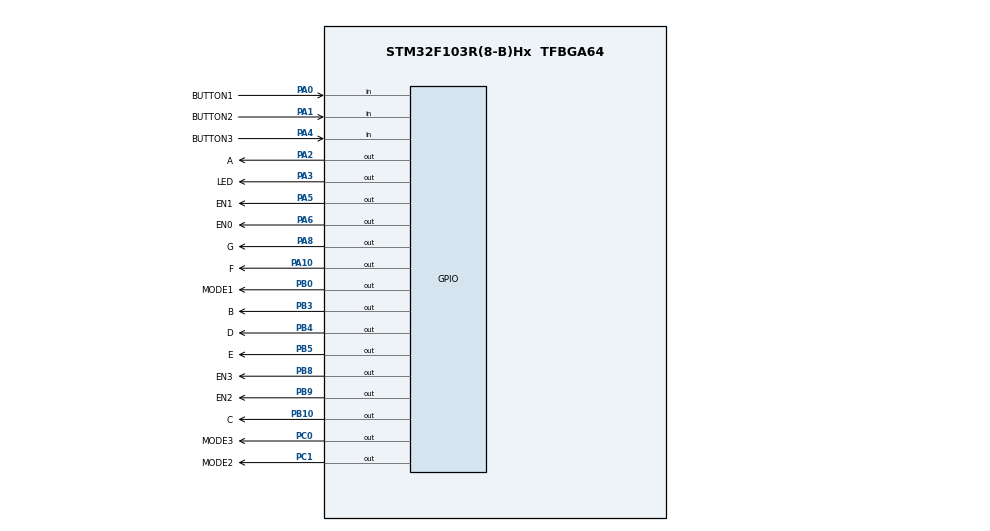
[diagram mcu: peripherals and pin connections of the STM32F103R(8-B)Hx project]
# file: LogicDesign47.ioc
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Mcu.Family=STM32F1
Mcu.Name=STM32F103R(8-B)Hx
Mcu.Package=TFBGA64
NVIC.PriorityGroup=NVIC_PRIORITYGROUP_4
NVIC.TIM2_IRQn=true\:0\:0\:false\:false\:true\:true\:true
PA0-WKUP.GPIO_Label=BUTTON1
PA0-WKUP.GPIO_PuPd=GPIO_PULLUP
PA0-WKUP.Signal=GPIO_Input
PA1.GPIO_Label=BUTTON2
PA1.GPIO_PuPd=GPIO_PULLUP
PA1.Signal=GPIO_Input
PA10.GPIO_Label=F
PA10.Signal=GPIO_Output
PA13.Mode=Serial_Wire
PA13.Signal=SYS_JTMS-SWDIO
PA14.Mode=Serial_Wire
PA14.Signal=SYS_JTCK-SWCLK
PA2.GPIO_Label=A
PA2.Signal=GPIO_Output
PA3.GPIO_Label=LED
PA3.Signal=GPIO_Output
PA4.GPIO_Label=BUTTON3
PA4.GPIO_PuPd=GPIO_PULLUP
PA4.Signal=GPIO_Input
PA5.GPIO_Label=EN1
PA5.Signal=GPIO_Output
PA6.GPIO_Label=EN0
PA6.Signal=GPIO_Output
PA8.GPIO_Label=G
PA8.Signal=GPIO_Output
PB0.GPIO_Label=MODE1
PB0.Signal=GPIO_Output
PB10.GPIO_Label=C
PB10.Signal=GPIO_Output
PB3.GPIO_Label=B
PB3.Signal=GPIO_Output
PB4.GPIO_Label=D
PB4.Signal=GPIO_Output
PB5.GPIO_Label=E
PB5.Signal=GPIO_Output
PB8.GPIO_Label=EN3
PB8.Signal=GPIO_Output
PB9.GPIO_Label=EN2
PB9.Signal=GPIO_Output
PC0.GPIO_Label=MODE3
PC0.Signal=GPIO_Output
PC1.GPIO_Label=MODE2
PC1.Signal=GPIO_Output
ProjectManager.HeapSize=0x200
ProjectManager.StackSize=0x400
ProjectManager.TargetToolchain=STM32CubeIDE
RCC.APB1Freq_Value=8000000
RCC.APB2Freq_Value=8000000
TIM2.Period=9
TIM2.Prescaler=7999
VP_TIM2_VS_ClockSourceINT.Mode=Internal
board=custom

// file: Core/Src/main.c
/* USER CODE BEGIN Header */
/**
  ******************************************************************************
  * @file           : main.c
  * @brief          : Main program body
  ******************************************************************************
  * @attention
  *
  * <h2><center>&copy; Copyright (c) 2023 STMicroelectronics.
  * All rights reserved.</center></h2>
  *
  * This software component is licensed by ST under BSD 3-Clause license,
  * the "License"; You may not use this file except in compliance with the
  * License. You may obtain a copy of the License at:
  *                        opensource.org/licenses/BSD-3-Clause
  *
  ******************************************************************************
  */
/* USER CODE END Header */
#include <driver.h>
#include "main.h"

/* USER CODE BEGIN Includes */
#include "software_timer.h"
#include "control_led_matrix.h"
#include "button.h"
/* USER CODE END Includes */

TIM_HandleTypeDef htim2;

void SystemClock_Config(void);
static void MX_GPIO_Init(void);
static void MX_TIM2_Init(void);

int main(void)
{

  /* MCU Configuration--------------------------------------------------------*/

  /* Reset of all peripherals, Initializes the Flash interface and the Systick. */
  HAL_Init();

  /* Configure the system clock */
  SystemClock_Config();

  /* Initialize all configured peripherals */
  MX_GPIO_Init();
  MX_TIM2_Init();
  /* USER CODE BEGIN 2 */
  HAL_TIM_Base_Start_IT (& htim2 );
  /* USER CODE END 2 */

  /* Infinite loop */
  /* USER CODE BEGIN WHILE */
  while (1)
  {
	 controlLedMatrix();
    /* USER CODE END WHILE */

  }
}

void SystemClock_Config(void)
{
  RCC_OscInitTypeDef RCC_OscInitStruct = {0};
  RCC_ClkInitTypeDef RCC_ClkInitStruct = {0};

  /** Initializes the RCC Oscillators according to the specified parameters
  * in the RCC_OscInitTypeDef structure.
  */
  RCC_OscInitStruct.OscillatorType = RCC_OSCILLATORTYPE_HSI;
  RCC_OscInitStruct.HSIState = RCC_HSI_ON;
  RCC_OscInitStruct.HSICalibrationValue = RCC_HSICALIBRATION_DEFAULT;
  RCC_OscInitStruct.PLL.PLLState = RCC_PLL_NONE;
  if (HAL_RCC_OscConfig(&RCC_OscInitStruct) != HAL_OK)
  {
    Error_Handler();
  }
  /** Initializes the CPU, AHB and APB buses clocks
  */
  RCC_ClkInitStruct.ClockType = RCC_CLOCKTYPE_HCLK|RCC_CLOCKTYPE_SYSCLK
                              |RCC_CLOCKTYPE_PCLK1|RCC_CLOCKTYPE_PCLK2;
  RCC_ClkInitStruct.SYSCLKSource = RCC_SYSCLKSOURCE_HSI;
  RCC_ClkInitStruct.AHBCLKDivider = RCC_SYSCLK_DIV1;
  RCC_ClkInitStruct.APB1CLKDivider = RCC_HCLK_DIV1;
  RCC_ClkInitStruct.APB2CLKDivider = RCC_HCLK_DIV1;

  if (HAL_RCC_ClockConfig(&RCC_ClkInitStruct, FLASH_LATENCY_0) != HAL_OK)
  {
    Error_Handler();
  }
}

static void MX_TIM2_Init(void)
{

  TIM_ClockConfigTypeDef sClockSourceConfig = {0};
  TIM_MasterConfigTypeDef sMasterConfig = {0};

  htim2.Instance = TIM2;
  htim2.Init.Prescaler = 799;
  htim2.Init.CounterMode = TIM_COUNTERMODE_UP;
  htim2.Init.Period = 9;
  htim2.Init.ClockDivision = TIM_CLOCKDIVISION_DIV1;
  htim2.Init.AutoReloadPreload = TIM_AUTORELOAD_PRELOAD_DISABLE;
  if (HAL_TIM_Base_Init(&htim2) != HAL_OK)
  {
    Error_Handler();
  }
  sClockSourceConfig.ClockSource = TIM_CLOCKSOURCE_INTERNAL;
  if (HAL_TIM_ConfigClockSource(&htim2, &sClockSourceConfig) != HAL_OK)
  {
    Error_Handler();
  }
  sMasterConfig.MasterOutputTrigger = TIM_TRGO_RESET;
  sMasterConfig.MasterSlaveMode = TIM_MASTERSLAVEMODE_DISABLE;
  if (HAL_TIMEx_MasterConfigSynchronization(&htim2, &sMasterConfig) != HAL_OK)
  {
    Error_Handler();
  }

}

static void MX_GPIO_Init(void)
{
  GPIO_InitTypeDef GPIO_InitStruct = {0};

  /* GPIO Ports Clock Enable */
  __HAL_RCC_GPIOC_CLK_ENABLE();
  __HAL_RCC_GPIOA_CLK_ENABLE();
  __HAL_RCC_GPIOB_CLK_ENABLE();

  /*Configure GPIO pin Output Level */
  HAL_GPIO_WritePin(GPIOA, LED_NORMAL_MODE_Pin|ROW1_Pin|ROW0_Pin|LED_CHAR_MODE_Pin
                          |ENM5_Pin|ENM4_Pin|ENM3_Pin|ROW7_Pin
                          |ENM0_Pin|ROW2_Pin, GPIO_PIN_RESET);

  /*Configure GPIO pin Output Level */
  HAL_GPIO_WritePin(GPIOB, LED_ANI_MODE_Pin|ROW6_Pin|ROW3_Pin|ROW5_Pin
                          |ROW4_Pin|ENM2_Pin|ENM7_Pin|ENM6_Pin, GPIO_PIN_RESET);

  /*Configure GPIO pin Output Level */
  HAL_GPIO_WritePin(ENM1_GPIO_Port, ENM1_Pin, GPIO_PIN_RESET);

  /*Configure GPIO pins : BUTTON_CHANGE_Pin BUTTON_MODE_Pin */
  GPIO_InitStruct.Pin = BUTTON_CHANGE_Pin|BUTTON_MODE_Pin;
  GPIO_InitStruct.Mode = GPIO_MODE_INPUT;
  GPIO_InitStruct.Pull = GPIO_PULLUP;
  HAL_GPIO_Init(GPIOC, &GPIO_InitStruct);

  /*Configure GPIO pins : LED_NORMAL_MODE_Pin ROW1_Pin ROW0_Pin LED_CHAR_MODE_Pin
                           ENM5_Pin ENM4_Pin ENM3_Pin ROW7_Pin
                           ENM0_Pin ROW2_Pin */
  GPIO_InitStruct.Pin = LED_NORMAL_MODE_Pin|ROW1_Pin|ROW0_Pin|LED_CHAR_MODE_Pin
                          |ENM5_Pin|ENM4_Pin|ENM3_Pin|ROW7_Pin
                          |ENM0_Pin|ROW2_Pin;
  GPIO_InitStruct.Mode = GPIO_MODE_OUTPUT_PP;
  GPIO_InitStruct.Pull = GPIO_NOPULL;
  GPIO_InitStruct.Speed = GPIO_SPEED_FREQ_LOW;
  HAL_GPIO_Init(GPIOA, &GPIO_InitStruct);

  /*Configure GPIO pins : LED_ANI_MODE_Pin ROW6_Pin ROW3_Pin ROW5_Pin
                           ROW4_Pin ENM2_Pin ENM7_Pin ENM6_Pin */
  GPIO_InitStruct.Pin = LED_ANI_MODE_Pin|ROW6_Pin|ROW3_Pin|ROW5_Pin
                          |ROW4_Pin|ENM2_Pin|ENM7_Pin|ENM6_Pin;
  GPIO_InitStruct.Mode = GPIO_MODE_OUTPUT_PP;
  GPIO_InitStruct.Pull = GPIO_NOPULL;
  GPIO_InitStruct.Speed = GPIO_SPEED_FREQ_LOW;
  HAL_GPIO_Init(GPIOB, &GPIO_InitStruct);

  /*Configure GPIO pin : ENM1_Pin */
  GPIO_InitStruct.Pin = ENM1_Pin;
  GPIO_InitStruct.Mode = GPIO_MODE_OUTPUT_PP;
  GPIO_InitStruct.Pull = GPIO_NOPULL;
  GPIO_InitStruct.Speed = GPIO_SPEED_FREQ_LOW;
  HAL_GPIO_Init(ENM1_GPIO_Port, &GPIO_InitStruct);

}

/* USER CODE BEGIN 4 */
void HAL_TIM_PeriodElapsedCallback ( TIM_HandleTypeDef * htim ){
	timerRun();
	get_key_input_all();
}
/* USER CODE END 4 */

void Error_Handler(void)
{
  __disable_irq();
  while (1)
  {
  }
}

/************************ (C) COPYRIGHT STMicroelectronics *****END OF FILE****/
